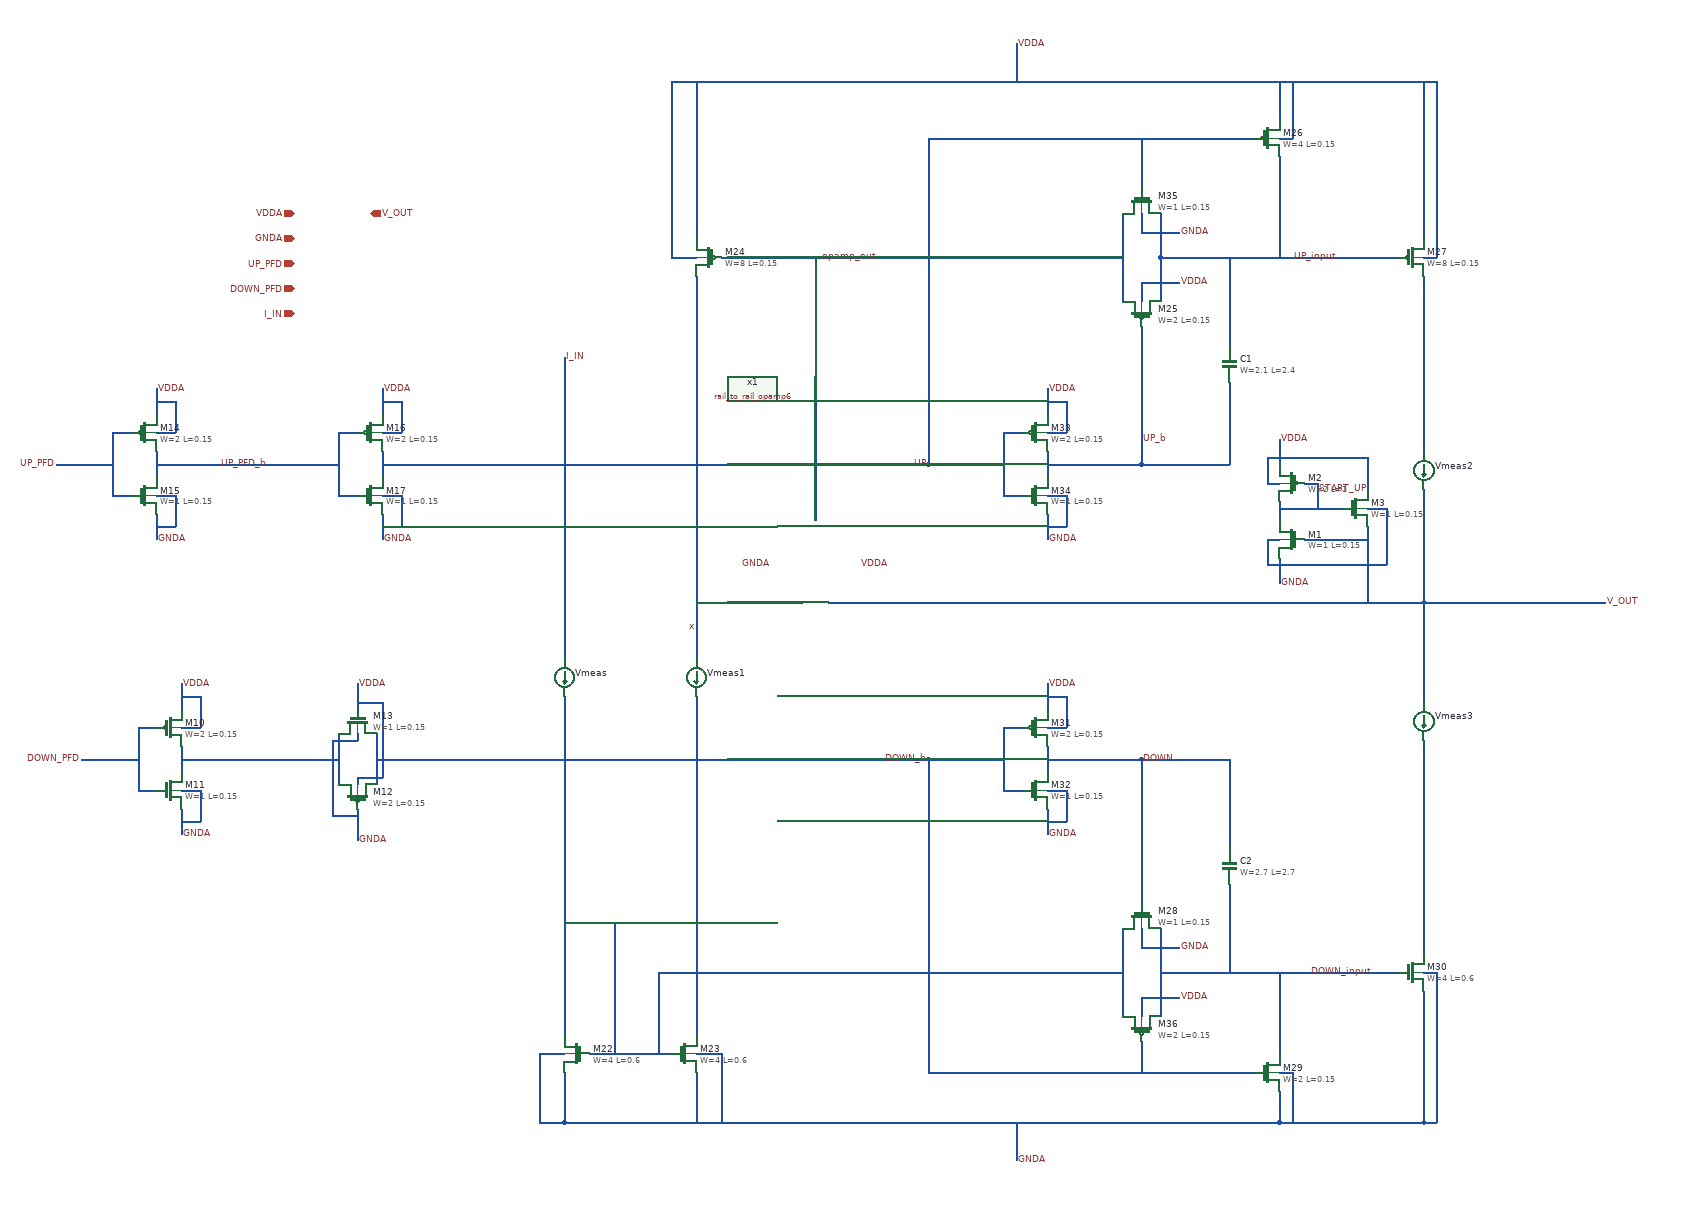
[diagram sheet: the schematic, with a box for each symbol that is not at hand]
v {xschem version=3.4.5 file_version=1.2
}
G {}
K {}
V {}
S {}
E {}
N 390 -1140 490 -1140 {
lab=UP_PFD_b}
N 430 -670 580 -670 {
lab=#net1}
N 130 -1140 170 -1140 {
lab=UP_PFD}
N 170 -670 210 -670 {
lab=DOWN_PFD}
N 580 -710 580 -630 {
lab=#net1}
N 640 -710 640 -630 {
lab=DOWN_b}
N 610 -790 610 -750 {
lab=VDDA}
N 610 -640 610 -630 {
lab=VDDA}
N 610 -640 650 -640 {
lab=VDDA}
N 650 -760 650 -640 {
lab=VDDA}
N 610 -760 650 -760 {
lab=VDDA}
N 610 -710 610 -700 {
lab=GNDA}
N 570 -700 610 -700 {
lab=GNDA}
N 570 -700 570 -580 {
lab=GNDA}
N 570 -580 610 -580 {
lab=GNDA}
N 610 -590 610 -540 {
lab=GNDA}
N 330 -690 330 -650 {
lab=#net1}
N 260 -720 290 -720 {
lab=DOWN_PFD}
N 260 -720 260 -620 {
lab=DOWN_PFD}
N 260 -620 290 -620 {
lab=DOWN_PFD}
N 330 -670 430 -670 {
lab=#net1}
N 210 -670 260 -670 {
lab=DOWN_PFD}
N 330 -590 330 -550 {
lab=GNDA}
N 330 -790 330 -750 {
lab=VDDA}
N 330 -720 360 -720 {
lab=VDDA}
N 360 -770 360 -720 {
lab=VDDA}
N 330 -770 360 -770 {
lab=VDDA}
N 330 -620 360 -620 {
lab=GNDA}
N 360 -620 360 -570 {
lab=GNDA}
N 330 -570 360 -570 {
lab=GNDA}
N 290 -1160 290 -1120 {
lab=UP_PFD_b}
N 220 -1190 250 -1190 {
lab=UP_PFD}
N 220 -1190 220 -1090 {
lab=UP_PFD}
N 220 -1090 250 -1090 {
lab=UP_PFD}
N 290 -1140 390 -1140 {
lab=UP_PFD_b}
N 170 -1140 220 -1140 {
lab=UP_PFD}
N 290 -1060 290 -1020 {
lab=GNDA}
N 290 -1260 290 -1220 {
lab=VDDA}
N 290 -1190 320 -1190 {
lab=VDDA}
N 320 -1240 320 -1190 {
lab=VDDA}
N 290 -1240 320 -1240 {
lab=VDDA}
N 290 -1090 320 -1090 {
lab=GNDA}
N 320 -1090 320 -1040 {
lab=GNDA}
N 290 -1040 320 -1040 {
lab=GNDA}
N 650 -1160 650 -1120 {
lab=UP}
N 580 -1190 610 -1190 {
lab=UP_PFD_b}
N 580 -1190 580 -1090 {
lab=UP_PFD_b}
N 580 -1090 610 -1090 {
lab=UP_PFD_b}
N 490 -1140 580 -1140 {
lab=UP_PFD_b}
N 650 -1060 650 -1020 {
lab=GNDA}
N 650 -1260 650 -1220 {
lab=VDDA}
N 650 -1190 680 -1190 {
lab=VDDA}
N 680 -1240 680 -1190 {
lab=VDDA}
N 650 -1240 680 -1240 {
lab=VDDA}
N 650 -1090 680 -1090 {
lab=GNDA}
N 680 -1090 680 -1040 {
lab=GNDA}
N 650 -1040 680 -1040 {
lab=GNDA}
N 650 -1140 1520 -1140 {
lab=UP}
N 2390 -920 2600 -920 {
lab=V_OUT}
N 980 -200 1110 -200 {
lab=#net2}
N 940 -170 940 -90 {
lab=GNDA}
N 940 -90 1440 -90 {
lab=GNDA}
N 900 -200 940 -200 {
lab=GNDA}
N 900 -200 900 -90 {
lab=GNDA}
N 900 -90 940 -90 {
lab=GNDA}
N 1150 -200 1190 -200 {
lab=GNDA}
N 1110 -1470 1150 -1470 {
lab=VDDA}
N 1440 -90 1480 -90 {
lab=GNDA}
N 1150 -1750 1150 -1500 {
lab=VDDA}
N 1110 -1750 1110 -1470 {
lab=VDDA}
N 2310 -1750 2310 -1500 {
lab=VDDA}
N 2080 -1750 2080 -1690 {
lab=VDDA}
N 2080 -1660 2100 -1660 {
lab=VDDA}
N 2100 -1750 2100 -1660 {
lab=VDDA}
N 2330 -1750 2330 -1470 {
lab=VDDA}
N 2310 -1470 2330 -1470 {
lab=VDDA}
N 2310 -1440 2310 -1160 {
lab=#net3}
N 1480 -90 2080 -90 {
lab=GNDA}
N 2080 -140 2080 -90 {
lab=GNDA}
N 2310 -330 2330 -330 {
lab=GNDA}
N 2310 -90 2330 -90 {
lab=GNDA}
N 1150 -1440 1150 -1040 {
lab=x}
N 1150 -920 1320 -920 {
lab=x}
N 1360 -920 2310 -920 {
lab=V_OUT}
N 1340 -1470 1340 -1050 {
lab=opamp_out}
N 1020 -410 1020 -200 {
lab=#net2}
N 940 -410 1020 -410 {
lab=#net2}
N 1190 -200 1190 -90 {
lab=GNDA}
N 1150 -170 1150 -90 {
lab=GNDA}
N 1090 -330 1830 -330 {
lab=#net2}
N 1860 -1360 1860 -1140 {
lab=UP_b}
N 1520 -1660 2040 -1660 {
lab=UP}
N 1520 -1660 1520 -1140 {
lab=UP}
N 2080 -1630 2080 -1470 {
lab=UP_input}
N 1890 -1470 2270 -1470 {
lab=UP_input}
N 1110 -1750 2330 -1750 {
lab=VDDA}
N 1800 -670 1860 -670 {
lab=DOWN}
N 1860 -670 1860 -440 {
lab=DOWN}
N 1520 -670 1520 -170 {
lab=DOWN_b}
N 1520 -170 2040 -170 {
lab=DOWN_b}
N 1710 -690 1710 -650 {
lab=DOWN}
N 1640 -720 1670 -720 {
lab=DOWN_b}
N 1640 -720 1640 -620 {
lab=DOWN_b}
N 1640 -620 1670 -620 {
lab=DOWN_b}
N 1710 -590 1710 -550 {
lab=GNDA}
N 1710 -790 1710 -750 {
lab=VDDA}
N 1710 -720 1740 -720 {
lab=VDDA}
N 1740 -770 1740 -720 {
lab=VDDA}
N 1710 -770 1740 -770 {
lab=VDDA}
N 1710 -620 1740 -620 {
lab=GNDA}
N 1740 -620 1740 -570 {
lab=GNDA}
N 1710 -570 1740 -570 {
lab=GNDA}
N 1710 -670 1800 -670 {
lab=DOWN}
N 1710 -1160 1710 -1120 {
lab=UP_b}
N 1640 -1190 1670 -1190 {
lab=UP}
N 1640 -1190 1640 -1090 {
lab=UP}
N 1640 -1090 1670 -1090 {
lab=UP}
N 1520 -1140 1640 -1140 {
lab=UP}
N 1710 -1060 1710 -1020 {
lab=GNDA}
N 1710 -1260 1710 -1220 {
lab=VDDA}
N 1710 -1190 1740 -1190 {
lab=VDDA}
N 1740 -1240 1740 -1190 {
lab=VDDA}
N 1710 -1240 1740 -1240 {
lab=VDDA}
N 1710 -1090 1740 -1090 {
lab=GNDA}
N 1740 -1090 1740 -1040 {
lab=GNDA}
N 1710 -1040 1740 -1040 {
lab=GNDA}
N 1710 -1140 1800 -1140 {
lab=UP_b}
N 1800 -1140 1860 -1140 {
lab=UP_b}
N 1150 -1040 1150 -980 {
lab=x}
N 940 -1310 940 -830 {
lab=I_IN}
N 1150 -980 1150 -830 {
lab=x}
N 1150 -450 1150 -230 {
lab=#net4}
N 1150 -770 1150 -510 {
lab=#net4}
N 940 -770 940 -510 {
lab=#net2}
N 940 -450 940 -230 {
lab=#net2}
N 1150 -510 1150 -450 {
lab=#net4}
N 940 -510 940 -450 {
lab=#net2}
N 1890 -1540 1890 -1470 {
lab=UP_input}
N 1830 -1540 1830 -1400 {
lab=opamp_out}
N 1890 -1470 1890 -1400 {
lab=UP_input}
N 1190 -1470 1830 -1470 {
lab=opamp_out}
N 2080 -90 2310 -90 {
lab=GNDA}
N 1890 -400 1890 -260 {
lab=DOWN_input}
N 1830 -400 1830 -260 {
lab=#net2}
N 1890 -330 2270 -330 {
lab=DOWN_input}
N 2310 -300 2310 -90 {
lab=GNDA}
N 2330 -330 2330 -90 {
lab=GNDA}
N 1090 -330 1090 -200 {
lab=#net2}
N 2080 -330 2080 -200 {
lab=DOWN_input}
N 2080 -170 2100 -170 {
lab=GNDA}
N 2100 -170 2100 -90 {
lab=GNDA}
N 1860 -220 1860 -170 {
lab=DOWN_b}
N 1860 -1660 1860 -1580 {
lab=UP}
N 2310 -700 2310 -360 {
lab=#net5}
N 2310 -920 2310 -760 {
lab=V_OUT}
N 2310 -1100 2310 -920 {
lab=V_OUT}
N 1860 -1140 2000 -1140 {
lab=UP_b}
N 2000 -1270 2000 -1140 {
lab=UP_b}
N 2000 -1470 2000 -1330 {
lab=UP_input}
N 2000 -670 2000 -530 {
lab=DOWN}
N 2000 -470 2000 -330 {
lab=DOWN_input}
N 1860 -670 2000 -670 {
lab=DOWN}
N 2310 -920 2390 -920 {
lab=V_OUT}
N 640 -670 1520 -670 {
lab=DOWN_b}
N 1520 -670 1640 -670 {
lab=DOWN_b}
N 1660 -1810 1660 -1750 {
lab=VDDA}
N 1660 -90 1660 -30 {
lab=GNDA}
N 1860 -290 1920 -290 {
lab=VDDA}
N 1860 -290 1860 -260 {
lab=VDDA}
N 1860 -400 1860 -370 {
lab=GNDA}
N 1860 -370 1920 -370 {
lab=GNDA}
N 1860 -1430 1920 -1430 {
lab=VDDA}
N 1860 -1430 1860 -1400 {
lab=VDDA}
N 1860 -1540 1860 -1510 {
lab=GNDA}
N 1860 -1510 1920 -1510 {
lab=GNDA}
N 2080 -1080 2080 -1050 {
lab=START_UP}
N 2060 -1110 2080 -1110 {
lab=VDDA}
N 2060 -1150 2060 -1110 {
lab=VDDA}
N 2060 -1150 2080 -1150 {
lab=VDDA}
N 2060 -1020 2080 -1020 {
lab=GNDA}
N 2060 -1020 2060 -980 {
lab=GNDA}
N 2060 -980 2080 -980 {
lab=GNDA}
N 2080 -1070 2180 -1070 {
lab=START_UP}
N 2220 -1070 2250 -1070 {
lab=GNDA}
N 2250 -1070 2250 -980 {
lab=GNDA}
N 2080 -980 2250 -980 {
lab=GNDA}
N 2120 -1110 2140 -1110 {
lab=START_UP}
N 2140 -1110 2140 -1070 {
lab=START_UP}
N 2220 -1040 2220 -920 {
lab=V_OUT}
N 2120 -1020 2220 -1020 {
lab=V_OUT}
N 2080 -1150 2220 -1150 {
lab=VDDA}
N 2220 -1150 2220 -1100 {
lab=VDDA}
N 2080 -990 2080 -950 {
lab=GNDA}
N 2080 -1180 2080 -1140 {
lab=VDDA}
C {devices/lab_wire.sym} 390 -1140 0 1 {name=p15 sig_type=std_logic lab=UP_PFD_b}
C {devices/lab_wire.sym} 130 -1140 0 0 {name=p2 sig_type=std_logic lab=UP_PFD}
C {devices/lab_wire.sym} 170 -670 2 1 {name=p7 sig_type=std_logic lab=DOWN_PFD}
C {sky130_fd_pr/pfet_01v8.sym} 610 -610 3 0 {name=M12
L=0.15
W=2
nf=2
mult=1
ad="'int((nf+1)/2) * W/nf * 0.29'" 
pd="'2*int((nf+1)/2) * (W/nf + 0.29)'"
as="'int((nf+2)/2) * W/nf * 0.29'" 
ps="'2*int((nf+2)/2) * (W/nf + 0.29)'"
nrd="'0.29 / W'" nrs="'0.29 / W'"
sa=0 sb=0 sd=0
model=pfet_01v8
spiceprefix=X
}
C {sky130_fd_pr/nfet_01v8.sym} 610 -730 1 0 {name=M13
L=0.15
W=1
nf=1 
mult=1
ad="'int((nf+1)/2) * W/nf * 0.29'" 
pd="'2*int((nf+1)/2) * (W/nf + 0.29)'"
as="'int((nf+2)/2) * W/nf * 0.29'" 
ps="'2*int((nf+2)/2) * (W/nf + 0.29)'"
nrd="'0.29 / W'" nrs="'0.29 / W'"
sa=0 sb=0 sd=0
model=nfet_01v8
spiceprefix=X
}
C {sky130_fd_pr/pfet_01v8.sym} 310 -720 0 0 {name=M10
L=0.15
W=2
nf=2
mult=1
ad="'int((nf+1)/2) * W/nf * 0.29'" 
pd="'2*int((nf+1)/2) * (W/nf + 0.29)'"
as="'int((nf+2)/2) * W/nf * 0.29'" 
ps="'2*int((nf+2)/2) * (W/nf + 0.29)'"
nrd="'0.29 / W'" nrs="'0.29 / W'"
sa=0 sb=0 sd=0
model=pfet_01v8
spiceprefix=X
}
C {sky130_fd_pr/nfet_01v8.sym} 310 -620 2 1 {name=M11
L=0.15
W=1
nf=1 
mult=1
ad="'int((nf+1)/2) * W/nf * 0.29'" 
pd="'2*int((nf+1)/2) * (W/nf + 0.29)'"
as="'int((nf+2)/2) * W/nf * 0.29'" 
ps="'2*int((nf+2)/2) * (W/nf + 0.29)'"
nrd="'0.29 / W'" nrs="'0.29 / W'"
sa=0 sb=0 sd=0
model=nfet_01v8
spiceprefix=X
}
C {sky130_fd_pr/pfet_01v8.sym} 270 -1190 0 0 {name=M14
L=0.15
W=2
nf=2
mult=1
ad="'int((nf+1)/2) * W/nf * 0.29'" 
pd="'2*int((nf+1)/2) * (W/nf + 0.29)'"
as="'int((nf+2)/2) * W/nf * 0.29'" 
ps="'2*int((nf+2)/2) * (W/nf + 0.29)'"
nrd="'0.29 / W'" nrs="'0.29 / W'"
sa=0 sb=0 sd=0
model=pfet_01v8
spiceprefix=X
}
C {sky130_fd_pr/nfet_01v8.sym} 270 -1090 2 1 {name=M15
L=0.15
W=1
nf=1 
mult=1
ad="'int((nf+1)/2) * W/nf * 0.29'" 
pd="'2*int((nf+1)/2) * (W/nf + 0.29)'"
as="'int((nf+2)/2) * W/nf * 0.29'" 
ps="'2*int((nf+2)/2) * (W/nf + 0.29)'"
nrd="'0.29 / W'" nrs="'0.29 / W'"
sa=0 sb=0 sd=0
model=nfet_01v8
spiceprefix=X
}
C {sky130_fd_pr/pfet_01v8.sym} 630 -1190 0 0 {name=M16
L=0.15
W=2
nf=2
mult=1
ad="'int((nf+1)/2) * W/nf * 0.29'" 
pd="'2*int((nf+1)/2) * (W/nf + 0.29)'"
as="'int((nf+2)/2) * W/nf * 0.29'" 
ps="'2*int((nf+2)/2) * (W/nf + 0.29)'"
nrd="'0.29 / W'" nrs="'0.29 / W'"
sa=0 sb=0 sd=0
model=pfet_01v8
spiceprefix=X
}
C {sky130_fd_pr/nfet_01v8.sym} 630 -1090 2 1 {name=M17
L=0.15
W=1
nf=1 
mult=1
ad="'int((nf+1)/2) * W/nf * 0.29'" 
pd="'2*int((nf+1)/2) * (W/nf + 0.29)'"
as="'int((nf+2)/2) * W/nf * 0.29'" 
ps="'2*int((nf+2)/2) * (W/nf + 0.29)'"
nrd="'0.29 / W'" nrs="'0.29 / W'"
sa=0 sb=0 sd=0
model=nfet_01v8
spiceprefix=X
}
C {devices/ipin.sym} 510 -1540 0 0 {name=p3 lab=VDDA}
C {devices/opin.sym} 630 -1540 0 0 {name=p11 lab=V_OUT}
C {devices/lab_pin.sym} 2600 -920 0 1 {name=p12 sig_type=std_logic lab=V_OUT}
C {devices/lab_pin.sym} 330 -550 0 1 {name=p27 sig_type=std_logic lab=GNDA}
C {devices/lab_pin.sym} 330 -790 0 1 {name=p28 sig_type=std_logic lab=VDDA}
C {devices/lab_pin.sym} 610 -540 0 1 {name=p29 sig_type=std_logic lab=GNDA}
C {devices/lab_pin.sym} 610 -790 0 1 {name=p30 sig_type=std_logic lab=VDDA}
C {devices/lab_pin.sym} 290 -1020 0 1 {name=p31 sig_type=std_logic lab=GNDA}
C {devices/lab_pin.sym} 290 -1260 0 1 {name=p32 sig_type=std_logic lab=VDDA}
C {devices/lab_pin.sym} 650 -1020 0 1 {name=p33 sig_type=std_logic lab=GNDA}
C {devices/lab_pin.sym} 650 -1260 0 1 {name=p34 sig_type=std_logic lab=VDDA}
C {devices/ipin.sym} 510 -1500 0 0 {name=p35 lab=GNDA}
C {devices/ipin.sym} 510 -1460 0 0 {name=p36 lab=UP_PFD}
C {devices/ipin.sym} 510 -1420 0 0 {name=p37 lab=DOWN_PFD}
C {devices/ipin.sym} 510 -1380 0 0 {name=p38 lab=I_IN}
C {sky130_fd_pr/nfet_01v8.sym} 960 -200 0 1 {name=M22
L=0.6
W=4
nf=1 
mult=1
ad="'int((nf+1)/2) * W/nf * 0.29'" 
pd="'2*int((nf+1)/2) * (W/nf + 0.29)'"
as="'int((nf+2)/2) * W/nf * 0.29'" 
ps="'2*int((nf+2)/2) * (W/nf + 0.29)'"
nrd="'0.29 / W'" nrs="'0.29 / W'"
sa=0 sb=0 sd=0
model=nfet_01v8
spiceprefix=X
}
C {sky130_fd_pr/nfet_01v8.sym} 1130 -200 0 0 {name=M23
L=0.6
W=4
nf=1 
mult=1
ad="'int((nf+1)/2) * W/nf * 0.29'" 
pd="'2*int((nf+1)/2) * (W/nf + 0.29)'"
as="'int((nf+2)/2) * W/nf * 0.29'" 
ps="'2*int((nf+2)/2) * (W/nf + 0.29)'"
nrd="'0.29 / W'" nrs="'0.29 / W'"
sa=0 sb=0 sd=0
model=nfet_01v8
spiceprefix=X
}
C {sky130_fd_pr/pfet_01v8.sym} 1170 -1470 2 0 {name=M24
L=0.15
W=8
nf=8
mult=1
ad="'int((nf+1)/2) * W/nf * 0.29'" 
pd="'2*int((nf+1)/2) * (W/nf + 0.29)'"
as="'int((nf+2)/2) * W/nf * 0.29'" 
ps="'2*int((nf+2)/2) * (W/nf + 0.29)'"
nrd="'0.29 / W'" nrs="'0.29 / W'"
sa=0 sb=0 sd=0
model=pfet_01v8
spiceprefix=X
}
C {devices/lab_wire.sym} 1150 -880 0 0 {name=p9 sig_type=std_logic lab=x}
C {sky130_fd_pr/pfet_01v8.sym} 1860 -1380 3 0 {name=M25
L=0.15
W=2
nf=2
mult=1
ad="'int((nf+1)/2) * W/nf * 0.29'" 
pd="'2*int((nf+1)/2) * (W/nf + 0.29)'"
as="'int((nf+2)/2) * W/nf * 0.29'" 
ps="'2*int((nf+2)/2) * (W/nf + 0.29)'"
nrd="'0.29 / W'" nrs="'0.29 / W'"
sa=0 sb=0 sd=0
model=pfet_01v8
spiceprefix=X
}
C {sky130_fd_pr/pfet_01v8.sym} 2060 -1660 0 0 {name=M26
L=0.15
W=4
nf=4
mult=1
ad="'int((nf+1)/2) * W/nf * 0.29'" 
pd="'2*int((nf+1)/2) * (W/nf + 0.29)'"
as="'int((nf+2)/2) * W/nf * 0.29'" 
ps="'2*int((nf+2)/2) * (W/nf + 0.29)'"
nrd="'0.29 / W'" nrs="'0.29 / W'"
sa=0 sb=0 sd=0
model=pfet_01v8
spiceprefix=X
}
C {sky130_fd_pr/pfet_01v8.sym} 2290 -1470 0 0 {name=M27
L=0.15
W=8
nf=8
mult=1
ad="'int((nf+1)/2) * W/nf * 0.29'" 
pd="'2*int((nf+1)/2) * (W/nf + 0.29)'"
as="'int((nf+2)/2) * W/nf * 0.29'" 
ps="'2*int((nf+2)/2) * (W/nf + 0.29)'"
nrd="'0.29 / W'" nrs="'0.29 / W'"
sa=0 sb=0 sd=0
model=pfet_01v8
spiceprefix=X
}
C {devices/lab_wire.sym} 1520 -1140 2 1 {name=p19 sig_type=std_logic lab=UP}
C {devices/lab_wire.sym} 1860 -1180 0 1 {name=p39 sig_type=std_logic lab=UP_b}
C {sky130_fd_pr/nfet_01v8.sym} 1860 -420 1 0 {name=M28
L=0.15
W=1
nf=1 
mult=1
ad="'int((nf+1)/2) * W/nf * 0.29'" 
pd="'2*int((nf+1)/2) * (W/nf + 0.29)'"
as="'int((nf+2)/2) * W/nf * 0.29'" 
ps="'2*int((nf+2)/2) * (W/nf + 0.29)'"
nrd="'0.29 / W'" nrs="'0.29 / W'"
sa=0 sb=0 sd=0
model=nfet_01v8
spiceprefix=X
}
C {sky130_fd_pr/nfet_01v8.sym} 2060 -170 0 0 {name=M29
L=0.15
W=2
nf=2 
mult=1
ad="'int((nf+1)/2) * W/nf * 0.29'" 
pd="'2*int((nf+1)/2) * (W/nf + 0.29)'"
as="'int((nf+2)/2) * W/nf * 0.29'" 
ps="'2*int((nf+2)/2) * (W/nf + 0.29)'"
nrd="'0.29 / W'" nrs="'0.29 / W'"
sa=0 sb=0 sd=0
model=nfet_01v8
spiceprefix=X
}
C {devices/lab_wire.sym} 1520 -670 0 0 {name=p40 sig_type=std_logic lab=DOWN_b}
C {sky130_fd_pr/nfet_01v8.sym} 2290 -330 0 0 {name=M30
L=0.6
W=4
nf=1 
mult=1
ad="'int((nf+1)/2) * W/nf * 0.29'" 
pd="'2*int((nf+1)/2) * (W/nf + 0.29)'"
as="'int((nf+2)/2) * W/nf * 0.29'" 
ps="'2*int((nf+2)/2) * (W/nf + 0.29)'"
nrd="'0.29 / W'" nrs="'0.29 / W'"
sa=0 sb=0 sd=0
model=nfet_01v8
spiceprefix=X
}
C {devices/lab_wire.sym} 2100 -1470 2 0 {name=p41 sig_type=std_logic lab=UP_input}
C {devices/lab_wire.sym} 2230 -330 0 0 {name=p42 sig_type=std_logic lab=DOWN_input}
C {devices/lab_wire.sym} 1440 -1470 0 0 {name=p43 sig_type=std_logic lab=opamp_out}
C {/foss/designs/my_design/projects/pll/charge_pump/xschem_ngspice/rail_to_rail_opamp6.sym} 1340 -980 1 1 {name=x1}
C {sky130_fd_pr/pfet_01v8.sym} 1690 -720 0 0 {name=M31
L=0.15
W=2
nf=2
mult=1
ad="'int((nf+1)/2) * W/nf * 0.29'" 
pd="'2*int((nf+1)/2) * (W/nf + 0.29)'"
as="'int((nf+2)/2) * W/nf * 0.29'" 
ps="'2*int((nf+2)/2) * (W/nf + 0.29)'"
nrd="'0.29 / W'" nrs="'0.29 / W'"
sa=0 sb=0 sd=0
model=pfet_01v8
spiceprefix=X
}
C {sky130_fd_pr/nfet_01v8.sym} 1690 -620 2 1 {name=M32
L=0.15
W=1
nf=1 
mult=1
ad="'int((nf+1)/2) * W/nf * 0.29'" 
pd="'2*int((nf+1)/2) * (W/nf + 0.29)'"
as="'int((nf+2)/2) * W/nf * 0.29'" 
ps="'2*int((nf+2)/2) * (W/nf + 0.29)'"
nrd="'0.29 / W'" nrs="'0.29 / W'"
sa=0 sb=0 sd=0
model=nfet_01v8
spiceprefix=X
}
C {sky130_fd_pr/pfet_01v8.sym} 1690 -1190 0 0 {name=M33
L=0.15
W=2
nf=2
mult=1
ad="'int((nf+1)/2) * W/nf * 0.29'" 
pd="'2*int((nf+1)/2) * (W/nf + 0.29)'"
as="'int((nf+2)/2) * W/nf * 0.29'" 
ps="'2*int((nf+2)/2) * (W/nf + 0.29)'"
nrd="'0.29 / W'" nrs="'0.29 / W'"
sa=0 sb=0 sd=0
model=pfet_01v8
spiceprefix=X
}
C {sky130_fd_pr/nfet_01v8.sym} 1690 -1090 2 1 {name=M34
L=0.15
W=1
nf=1 
mult=1
ad="'int((nf+1)/2) * W/nf * 0.29'" 
pd="'2*int((nf+1)/2) * (W/nf + 0.29)'"
as="'int((nf+2)/2) * W/nf * 0.29'" 
ps="'2*int((nf+2)/2) * (W/nf + 0.29)'"
nrd="'0.29 / W'" nrs="'0.29 / W'"
sa=0 sb=0 sd=0
model=nfet_01v8
spiceprefix=X
}
C {devices/lab_wire.sym} 940 -1310 0 1 {name=p44 sig_type=std_logic lab=I_IN}
C {devices/ammeter.sym} 940 -800 0 0 {name=Vmeas savecurrent=true spice_ignore=0}
C {devices/ammeter.sym} 1150 -800 0 0 {name=Vmeas1 savecurrent=true spice_ignore=0}
C {devices/lab_wire.sym} 1860 -670 0 1 {name=p45 sig_type=std_logic lab=DOWN}
C {devices/ammeter.sym} 2310 -1130 0 0 {name=Vmeas2 savecurrent=true spice_ignore=0}
C {devices/ammeter.sym} 2310 -730 0 0 {name=Vmeas3 savecurrent=true spice_ignore=0}
C {sky130_fd_pr/nfet_01v8.sym} 1860 -1560 1 0 {name=M35
L=0.15
W=1
nf=1 
mult=1
ad="'int((nf+1)/2) * W/nf * 0.29'" 
pd="'2*int((nf+1)/2) * (W/nf + 0.29)'"
as="'int((nf+2)/2) * W/nf * 0.29'" 
ps="'2*int((nf+2)/2) * (W/nf + 0.29)'"
nrd="'0.29 / W'" nrs="'0.29 / W'"
sa=0 sb=0 sd=0
model=nfet_01v8
spiceprefix=X
}
C {sky130_fd_pr/pfet_01v8.sym} 1860 -240 3 0 {name=M36
L=0.15
W=2
nf=2
mult=1
ad="'int((nf+1)/2) * W/nf * 0.29'" 
pd="'2*int((nf+1)/2) * (W/nf + 0.29)'"
as="'int((nf+2)/2) * W/nf * 0.29'" 
ps="'2*int((nf+2)/2) * (W/nf + 0.29)'"
nrd="'0.29 / W'" nrs="'0.29 / W'"
sa=0 sb=0 sd=0
model=pfet_01v8
spiceprefix=X
}
C {sky130_fd_pr/cap_mim_m3_1.sym} 2000 -1300 0 0 {name=C1 model=cap_mim_m3_1 W=2.1 L=2.4 MF=1 spiceprefix=X}
C {sky130_fd_pr/cap_mim_m3_1.sym} 2000 -500 0 0 {name=C2 model=cap_mim_m3_1 W=2.7 L=2.7 MF=1 spiceprefix=X}
C {devices/lab_pin.sym} 1660 -1810 0 1 {name=p26 sig_type=std_logic lab=VDDA}
C {devices/lab_pin.sym} 1660 -30 0 1 {name=p18 sig_type=std_logic lab=GNDA}
C {devices/lab_pin.sym} 1410 -980 0 1 {name=p1 sig_type=std_logic lab=VDDA}
C {devices/lab_pin.sym} 1270 -980 0 0 {name=p4 sig_type=std_logic lab=GNDA}
C {devices/lab_pin.sym} 1710 -1260 0 1 {name=p5 sig_type=std_logic lab=VDDA}
C {devices/lab_pin.sym} 1710 -1020 0 1 {name=p6 sig_type=std_logic lab=GNDA}
C {devices/lab_pin.sym} 1710 -790 0 1 {name=p8 sig_type=std_logic lab=VDDA}
C {devices/lab_pin.sym} 1710 -550 0 1 {name=p10 sig_type=std_logic lab=GNDA}
C {devices/lab_pin.sym} 1920 -290 0 1 {name=p13 sig_type=std_logic lab=VDDA}
C {devices/lab_pin.sym} 1920 -370 0 1 {name=p14 sig_type=std_logic lab=GNDA}
C {devices/lab_pin.sym} 1920 -1430 0 1 {name=p16 sig_type=std_logic lab=VDDA}
C {devices/lab_pin.sym} 1920 -1510 0 1 {name=p17 sig_type=std_logic lab=GNDA}
C {sky130_fd_pr/nfet_01v8.sym} 2100 -1020 0 1 {name=M1
L=0.15
W=1
nf=1 
mult=1
ad="'int((nf+1)/2) * W/nf * 0.29'" 
pd="'2*int((nf+1)/2) * (W/nf + 0.29)'"
as="'int((nf+2)/2) * W/nf * 0.29'" 
ps="'2*int((nf+2)/2) * (W/nf + 0.29)'"
nrd="'0.29 / W'" nrs="'0.29 / W'"
sa=0 sb=0 sd=0
model=nfet_01v8
spiceprefix=X
}
C {sky130_fd_pr/pfet_01v8.sym} 2100 -1110 0 1 {name=M2
L=1
W=2
nf=1
mult=1
ad="'int((nf+1)/2) * W/nf * 0.29'" 
pd="'2*int((nf+1)/2) * (W/nf + 0.29)'"
as="'int((nf+2)/2) * W/nf * 0.29'" 
ps="'2*int((nf+2)/2) * (W/nf + 0.29)'"
nrd="'0.29 / W'" nrs="'0.29 / W'"
sa=0 sb=0 sd=0
model=pfet_01v8
spiceprefix=X
}
C {sky130_fd_pr/nfet_01v8.sym} 2200 -1070 0 0 {name=M3
L=0.15
W=1
nf=1 
mult=1
ad="'int((nf+1)/2) * W/nf * 0.29'" 
pd="'2*int((nf+1)/2) * (W/nf + 0.29)'"
as="'int((nf+2)/2) * W/nf * 0.29'" 
ps="'2*int((nf+2)/2) * (W/nf + 0.29)'"
nrd="'0.29 / W'" nrs="'0.29 / W'"
sa=0 sb=0 sd=0
model=nfet_01v8
spiceprefix=X
}
C {devices/lab_wire.sym} 2140 -1100 0 1 {name=p20 sig_type=std_logic lab=START_UP}
C {devices/lab_pin.sym} 2080 -1180 0 1 {name=p21 sig_type=std_logic lab=VDDA}
C {devices/lab_pin.sym} 2080 -950 0 1 {name=p22 sig_type=std_logic lab=GNDA}
